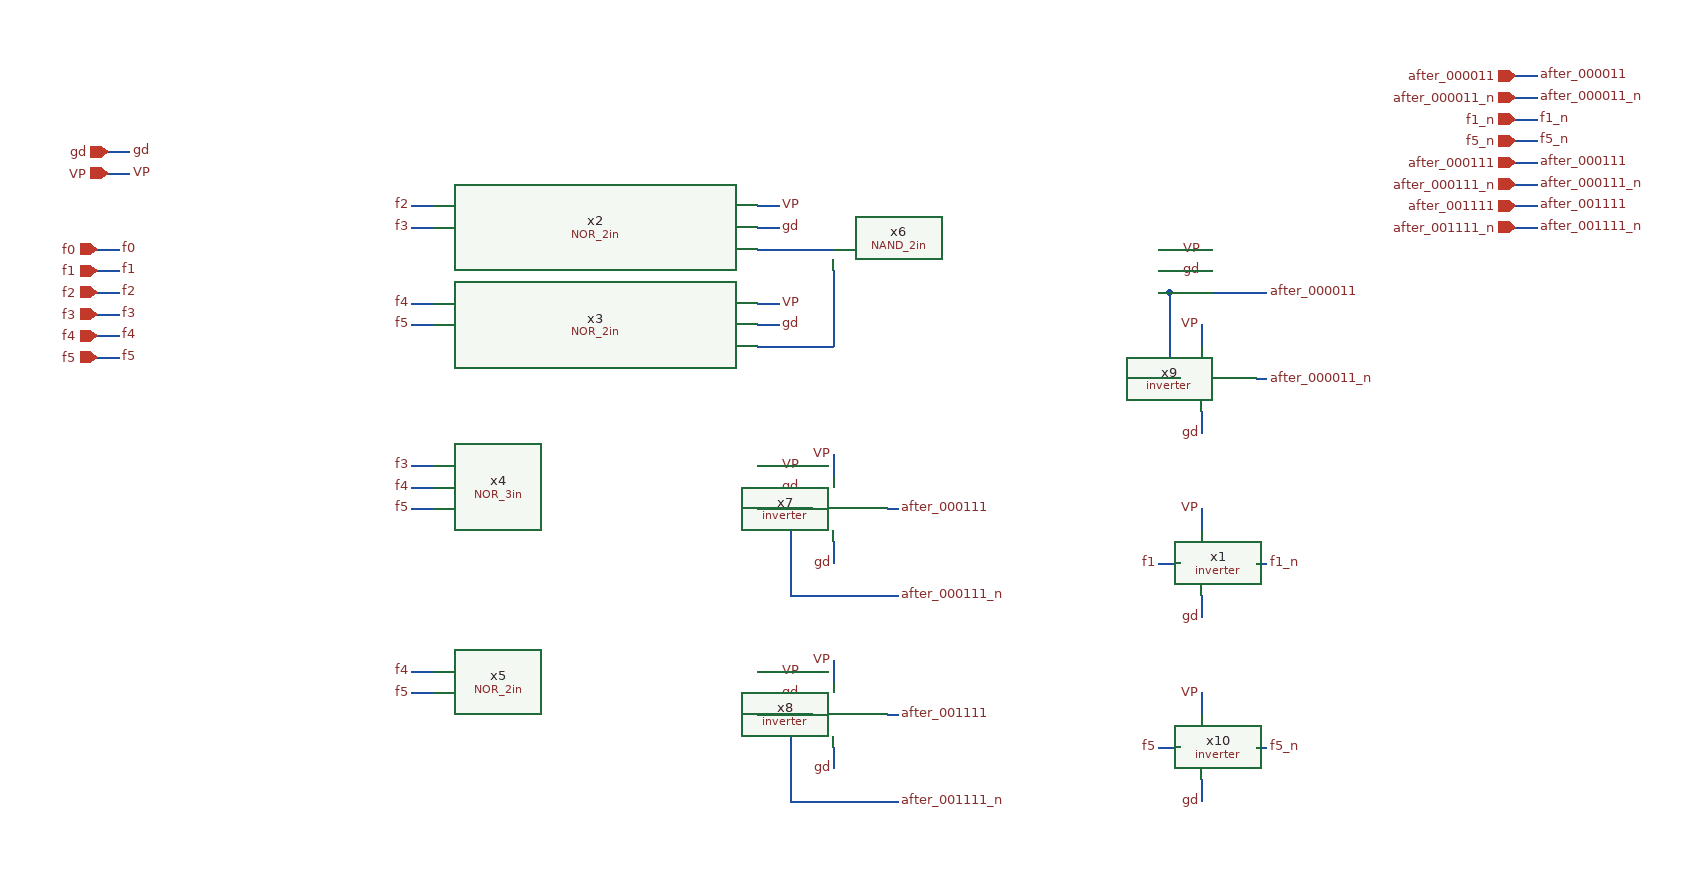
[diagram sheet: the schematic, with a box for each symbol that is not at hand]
v {xschem version=3.4.8RC file_version=1.3}
G {}
K {}
V {}
S {}
F {}
E {}
N 1130 -1260 1150 -1260 {lab=gd}
N 1130 -1280 1150 -1280 {lab=VP}
N 1130 -1170 1150 -1170 {lab=gd}
N 1130 -1190 1150 -1190 {lab=VP}
N 1130 -1020 1150 -1020 {lab=gd}
N 1130 -1040 1150 -1040 {lab=VP}
N 1130 -830 1150 -830 {lab=gd}
N 1130 -850 1150 -850 {lab=VP}
N 1130 -1240 1200 -1240 {lab=#net1}
N 1200 -1220 1200 -1150 {lab=#net2}
N 1130 -1150 1200 -1150 {lab=#net2}
N 1500 -1220 1520 -1220 {lab=gd}
N 1500 -1240 1520 -1240 {lab=VP}
N 1200 -970 1200 -950 {lab=gd}
N 1200 -1050 1200 -1030 {lab=VP}
N 1160 -1000 1180 -1000 {lab=after_000111_n}
N 1160 -1000 1160 -920 {lab=after_000111_n}
N 1130 -1000 1160 -1000 {lab=after_000111_n}
N 1160 -920 1260 -920 {lab=after_000111_n}
N 1200 -780 1200 -760 {lab=gd}
N 1200 -860 1200 -840 {lab=VP}
N 1160 -810 1180 -810 {lab=after_001111_n}
N 1160 -810 1160 -730 {lab=after_001111_n}
N 1130 -810 1160 -810 {lab=after_001111_n}
N 1160 -730 1260 -730 {lab=after_001111_n}
N 1250 -810 1260 -810 {lab=after_001111}
N 1250 -1000 1260 -1000 {lab=after_000111}
N 810 -1280 830 -1280 {lab=f2}
N 810 -1260 830 -1260 {lab=f3}
N 810 -1190 830 -1190 {lab=f4}
N 810 -1170 830 -1170 {lab=f5}
N 810 -1040 830 -1040 {lab=f3}
N 810 -1020 830 -1020 {lab=f4}
N 810 -1000 830 -1000 {lab=f5}
N 810 -850 830 -850 {lab=f4}
N 810 -830 830 -830 {lab=f5}
N 1510 -1200 1600 -1200 {lab=after_000011}
N 1540 -1090 1540 -1070 {lab=gd}
N 1540 -1170 1540 -1150 {lab=VP}
N 1590 -1120 1600 -1120 {lab=after_000011_n}
N 1510 -1200 1510 -1120 {lab=after_000011}
N 1500 -1200 1510 -1200 {lab=after_000011}
N 1510 -1120 1520 -1120 {lab=after_000011}
N 1540 -920 1540 -900 {lab=gd}
N 1540 -1000 1540 -980 {lab=VP}
N 1500 -950 1520 -950 {lab=f1}
N 1590 -950 1600 -950 {lab=f1_n}
N 1540 -750 1540 -730 {lab=gd}
N 1540 -830 1540 -810 {lab=VP}
N 1500 -780 1520 -780 {lab=f5}
N 1590 -780 1600 -780 {lab=f5_n}
N 520 -1240 540 -1240 {lab=f0}
N 520 -1220 540 -1220 {lab=f1}
N 520 -1200 540 -1200 {lab=f2}
N 520 -1180 540 -1180 {lab=f3}
N 520 -1160 540 -1160 {lab=f4}
N 520 -1140 540 -1140 {lab=f5}
N 530 -1330 550 -1330 {lab=gd}
N 530 -1310 550 -1310 {lab=VP}
N 1830 -1380 1850 -1380 {lab=after_000011_n}
N 1830 -1360 1850 -1360 {lab=f1_n}
N 1830 -1400 1850 -1400 {lab=after_000011}
N 1830 -1340 1850 -1340 {lab=f5_n}
N 1830 -1320 1850 -1320 {lab=after_000111}
N 1830 -1280 1850 -1280 {lab=after_001111}
N 1830 -1260 1850 -1260 {lab=VCO5_11_sel}
N 1830 -1300 1850 -1300 {lab=after_000111_n}
C {NOR_2in.sym} 980 -1260 0 0 {name=x2}
C {NOR_2in.sym} 980 -1170 0 0 {name=x3}
C {NOR_3in.sym} 980 -1020 0 0 {name=x4}
C {NOR_2in.sym} 980 -830 0 0 {name=x5}
C {lab_wire.sym} 1150 -1280 2 0 {name=p34 sig_type=std_logic lab=VP}
C {lab_wire.sym} 1150 -1260 2 0 {name=p35 sig_type=std_logic lab=gd}
C {lab_wire.sym} 1150 -1190 2 0 {name=p36 sig_type=std_logic lab=VP}
C {lab_wire.sym} 1150 -1170 2 0 {name=p37 sig_type=std_logic lab=gd}
C {lab_wire.sym} 1150 -1040 2 0 {name=p38 sig_type=std_logic lab=VP}
C {lab_wire.sym} 1150 -1020 2 0 {name=p39 sig_type=std_logic lab=gd}
C {lab_wire.sym} 1150 -850 2 0 {name=p40 sig_type=std_logic lab=VP}
C {lab_wire.sym} 1150 -830 2 0 {name=p41 sig_type=std_logic lab=gd}
C {NAND_2in.sym} 1350 -1220 0 0 {name=x6}
C {lab_wire.sym} 1520 -1240 2 0 {name=p42 sig_type=std_logic lab=VP}
C {lab_wire.sym} 1520 -1220 2 0 {name=p43 sig_type=std_logic lab=gd}
C {inverter.sym} 1200 -1000 0 0 {name=x7}
C {lab_wire.sym} 1200 -950 3 0 {name=p44 sig_type=std_logic lab=gd}
C {lab_wire.sym} 1200 -1050 1 0 {name=p45 sig_type=std_logic lab=VP}
C {inverter.sym} 1200 -810 0 0 {name=x8}
C {lab_wire.sym} 1200 -760 3 0 {name=p47 sig_type=std_logic lab=gd}
C {lab_wire.sym} 1200 -860 1 0 {name=p48 sig_type=std_logic lab=VP}
C {lab_wire.sym} 810 -1280 0 0 {name=p49 sig_type=std_logic lab=f2}
C {lab_wire.sym} 810 -1040 0 0 {name=p50 sig_type=std_logic lab=f3}
C {lab_wire.sym} 810 -1020 0 0 {name=p51 sig_type=std_logic lab=f4}
C {lab_wire.sym} 810 -1000 0 0 {name=p52 sig_type=std_logic lab=f5}
C {lab_wire.sym} 810 -1190 0 0 {name=p62 sig_type=std_logic lab=f4}
C {lab_wire.sym} 810 -1170 0 0 {name=p64 sig_type=std_logic lab=f5}
C {lab_wire.sym} 810 -1260 0 0 {name=p65 sig_type=std_logic lab=f3}
C {lab_wire.sym} 810 -850 0 0 {name=p66 sig_type=std_logic lab=f4}
C {lab_wire.sym} 810 -830 0 0 {name=p67 sig_type=std_logic lab=f5}
C {inverter.sym} 1540 -1120 0 0 {name=x9}
C {lab_wire.sym} 1540 -1070 3 0 {name=p68 sig_type=std_logic lab=gd}
C {lab_wire.sym} 1540 -1170 1 0 {name=p69 sig_type=std_logic lab=VP}
C {lab_wire.sym} 1600 -1200 2 0 {name=p70 sig_type=std_logic lab=after_000011}
C {lab_wire.sym} 1600 -1120 2 0 {name=p71 sig_type=std_logic lab=after_000011_n}
C {lab_wire.sym} 1260 -1000 2 0 {name=p72 sig_type=std_logic lab=after_000111}
C {lab_wire.sym} 1260 -920 2 0 {name=p73 sig_type=std_logic lab=after_000111_n}
C {lab_wire.sym} 1260 -810 2 0 {name=p74 sig_type=std_logic lab=after_001111}
C {lab_wire.sym} 1260 -730 2 0 {name=p75 sig_type=std_logic lab=after_001111_n}
C {inverter.sym} 1540 -950 0 0 {name=x1}
C {lab_wire.sym} 1540 -900 3 0 {name=p76 sig_type=std_logic lab=gd}
C {lab_wire.sym} 1540 -1000 1 0 {name=p77 sig_type=std_logic lab=VP}
C {lab_wire.sym} 1600 -950 2 0 {name=p78 sig_type=std_logic lab=f1_n}
C {inverter.sym} 1540 -780 0 0 {name=x10}
C {lab_wire.sym} 1540 -730 3 0 {name=p79 sig_type=std_logic lab=gd}
C {lab_wire.sym} 1540 -830 1 0 {name=p80 sig_type=std_logic lab=VP}
C {lab_wire.sym} 1600 -780 2 0 {name=p81 sig_type=std_logic lab=f5_n}
C {lab_wire.sym} 1500 -950 0 0 {name=p82 sig_type=std_logic lab=f1}
C {lab_wire.sym} 1500 -780 0 0 {name=p83 sig_type=std_logic lab=f5}
C {ipin.sym} 520 -1240 0 0 {name=p59 lab=f0}
C {lab_wire.sym} 540 -1240 2 0 {name=p60 sig_type=std_logic lab=f0}
C {ipin.sym} 520 -1220 0 0 {name=p61 lab=f1}
C {lab_wire.sym} 540 -1220 2 0 {name=p63 sig_type=std_logic lab=f1}
C {ipin.sym} 520 -1200 0 0 {name=p19 lab=f2}
C {lab_wire.sym} 540 -1200 2 0 {name=p22 sig_type=std_logic lab=f2}
C {ipin.sym} 520 -1180 0 0 {name=p23 lab=f3}
C {lab_wire.sym} 540 -1180 2 0 {name=p24 sig_type=std_logic lab=f3}
C {ipin.sym} 520 -1160 0 0 {name=p25 lab=f4}
C {lab_wire.sym} 540 -1160 2 0 {name=p26 sig_type=std_logic lab=f4}
C {ipin.sym} 520 -1140 0 0 {name=p27 lab=f5}
C {lab_wire.sym} 540 -1140 2 0 {name=p28 sig_type=std_logic lab=f5}
C {iopin.sym} 530 -1330 2 0 {name=p46 lab=gd}
C {lab_wire.sym} 550 -1330 2 0 {name=p53 sig_type=std_logic lab=gd}
C {iopin.sym} 530 -1310 2 0 {name=p54 lab=VP}
C {lab_wire.sym} 550 -1310 2 0 {name=p1 sig_type=std_logic lab=VP}
C {opin.sym} 1830 -1380 0 1 {name=p6 lab=after_000011_n}
C {lab_wire.sym} 1850 -1380 2 0 {name=p7 sig_type=std_logic lab=after_000011_n}
C {opin.sym} 1830 -1360 0 1 {name=p8 lab=f1_n}
C {lab_wire.sym} 1850 -1360 2 0 {name=p9 sig_type=std_logic lab=f1_n}
C {opin.sym} 1830 -1400 0 1 {name=p14 lab=after_000011}
C {lab_wire.sym} 1850 -1400 2 0 {name=p15 sig_type=std_logic lab=after_000011}
C {opin.sym} 1830 -1340 0 1 {name=p10 lab=f5_n}
C {lab_wire.sym} 1850 -1340 2 0 {name=p11 sig_type=std_logic lab=f5_n}
C {opin.sym} 1830 -1320 0 1 {name=p12 lab=after_000111}
C {lab_wire.sym} 1850 -1320 2 0 {name=p13 sig_type=std_logic lab=after_000111}
C {opin.sym} 1830 -1300 0 1 {name=p3 lab=after_000111_n}
C {lab_wire.sym} 1850 -1300 2 0 {name=p4 sig_type=std_logic lab=after_000111_n}
C {opin.sym} 1830 -1280 0 1 {name=p5 lab=after_001111}
C {lab_wire.sym} 1850 -1280 2 0 {name=p16 sig_type=std_logic lab=after_001111}
C {opin.sym} 1830 -1260 0 1 {name=p17 lab=after_001111_n}
C {lab_wire.sym} 1850 -1260 2 0 {name=p18 sig_type=std_logic lab=after_001111_n}
